VERSION 5.7 ;
  NOWIREEXTENSIONATPIN ON ;
  DIVIDERCHAR "/" ;
  BUSBITCHARS "[]" ;
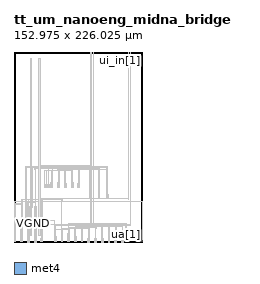
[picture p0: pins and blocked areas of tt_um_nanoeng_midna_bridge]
MACRO tt_um_nanoeng_midna_bridge
  CLASS BLOCK ;
  FOREIGN tt_um_nanoeng_midna_bridge ;
  ORIGIN 0.215 0.265 ;
  SIZE 152.975 BY 226.025 ;
  PIN ua[0]
    DIRECTION INOUT ;
    USE ANALOG ;
    PORT
      LAYER met4 ;
        RECT 151.810 0.000 152.710 1.000 ;
    END
  END ua[0]
  PIN ua[1]
    DIRECTION INOUT ;
    USE ANALOG ;
    ANTENNAGATEAREA 1.200000 ;
    PORT
      LAYER met4 ;
        RECT 132.490 0.000 133.390 1.000 ;
    END
  END ua[1]
  PIN ui_in[0]
    DIRECTION INPUT ;
    USE SIGNAL ;
    ANTENNAGATEAREA 1.800000 ;
    PORT
      LAYER met4 ;
        RECT 138.310 224.760 138.610 225.760 ;
    END
  END ui_in[0]
  PIN ui_in[1]
    DIRECTION INPUT ;
    USE SIGNAL ;
    ANTENNAGATEAREA 0.300000 ;
    PORT
      LAYER met4 ;
        RECT 135.550 224.760 135.850 225.760 ;
    END
  END ui_in[1]
  PIN uo_out[0]
    DIRECTION OUTPUT ;
    USE SIGNAL ;
    ANTENNAGATEAREA 1.200000 ;
    PORT
      LAYER met4 ;
        RECT 94.150 224.760 94.450 225.760 ;
    END
  END uo_out[0]
  PIN uo_out[1]
    DIRECTION OUTPUT ;
    USE SIGNAL ;
    ANTENNAGATEAREA 1.200000 ;
    PORT
      LAYER met4 ;
        RECT 91.390 224.760 91.690 225.760 ;
    END
  END uo_out[1]
  PIN VGND
    DIRECTION INPUT ;
    USE GROUND ;
    PORT
      LAYER met4 ;
        RECT 19.250 21.300 20.750 22.700 ;
    END
  END VGND
  PIN VPWR
    DIRECTION INPUT ;
    USE POWER ;
    PORT
      LAYER met4 ;
        RECT 29.250 21.300 30.750 22.700 ;
    END
  END VPWR
  OBS
      LAYER pwell ;
        RECT 35.785 64.785 41.645 67.785 ;
      LAYER nwell ;
        RECT 43.735 64.735 45.995 70.925 ;
        RECT 51.735 64.735 53.995 70.925 ;
      LAYER pwell ;
        RECT 59.785 64.785 61.795 68.785 ;
      LAYER nwell ;
        RECT 67.735 64.735 69.995 70.925 ;
      LAYER pwell ;
        RECT 75.785 64.785 77.795 68.785 ;
      LAYER nwell ;
        RECT 89.735 52.735 91.995 64.925 ;
        RECT 99.735 52.735 101.845 64.925 ;
      LAYER pwell ;
        RECT 109.785 52.785 111.795 56.785 ;
        RECT -0.215 -0.215 1.795 21.785 ;
        RECT 7.785 -0.215 9.795 21.785 ;
      LAYER nwell ;
        RECT 15.735 -0.265 17.845 41.925 ;
        RECT 23.735 -0.265 25.995 41.925 ;
      LAYER pwell ;
        RECT 31.785 -0.215 33.795 3.785 ;
        RECT 47.785 -0.215 49.795 5.785 ;
        RECT 55.785 -0.215 57.795 9.785 ;
        RECT 63.785 -0.215 65.795 9.785 ;
        RECT 71.785 -0.215 73.795 5.785 ;
        RECT 79.785 -0.215 81.795 5.785 ;
      LAYER nwell ;
        RECT 87.735 -0.265 89.845 3.925 ;
        RECT 95.735 -0.265 97.845 3.925 ;
        RECT 103.735 -0.265 105.845 3.925 ;
        RECT 111.735 -0.265 113.845 3.925 ;
        RECT 119.735 -0.265 121.845 5.925 ;
        RECT 127.735 -0.265 129.845 5.925 ;
      LAYER li1 ;
        RECT 43.915 70.575 45.815 70.745 ;
        RECT 35.915 67.485 41.515 67.655 ;
        RECT 35.915 65.085 36.085 67.485 ;
        RECT 36.715 66.975 40.715 67.145 ;
        RECT 36.485 65.765 36.655 66.805 ;
        RECT 40.775 65.765 40.945 66.805 ;
        RECT 36.715 65.425 40.715 65.595 ;
        RECT 41.345 65.085 41.515 67.485 ;
        RECT 35.915 64.915 41.515 65.085 ;
        RECT 43.915 65.085 44.085 70.575 ;
        RECT 44.700 70.065 45.030 70.235 ;
        RECT 44.485 65.810 44.655 69.850 ;
        RECT 45.075 65.810 45.245 69.850 ;
        RECT 44.700 65.425 45.030 65.595 ;
        RECT 45.645 65.085 45.815 70.575 ;
        RECT 43.915 64.915 45.815 65.085 ;
        RECT 51.915 70.575 53.815 70.745 ;
        RECT 51.915 65.085 52.085 70.575 ;
        RECT 52.700 70.065 53.030 70.235 ;
        RECT 52.485 65.810 52.655 69.850 ;
        RECT 53.075 65.810 53.245 69.850 ;
        RECT 52.700 65.425 53.030 65.595 ;
        RECT 53.645 65.085 53.815 70.575 ;
        RECT 67.915 70.575 69.815 70.745 ;
        RECT 51.915 64.915 53.815 65.085 ;
        RECT 59.915 68.485 61.665 68.655 ;
        RECT 59.915 65.085 60.085 68.485 ;
        RECT 60.625 67.975 60.955 68.145 ;
        RECT 60.485 65.765 60.655 67.805 ;
        RECT 60.925 65.765 61.095 67.805 ;
        RECT 60.625 65.425 60.955 65.595 ;
        RECT 61.495 65.085 61.665 68.485 ;
        RECT 59.915 64.915 61.665 65.085 ;
        RECT 67.915 65.085 68.085 70.575 ;
        RECT 68.700 70.065 69.030 70.235 ;
        RECT 68.485 65.810 68.655 69.850 ;
        RECT 69.075 65.810 69.245 69.850 ;
        RECT 68.700 65.425 69.030 65.595 ;
        RECT 69.645 65.085 69.815 70.575 ;
        RECT 67.915 64.915 69.815 65.085 ;
        RECT 75.915 68.485 77.665 68.655 ;
        RECT 75.915 65.085 76.085 68.485 ;
        RECT 76.625 67.975 76.955 68.145 ;
        RECT 76.485 65.765 76.655 67.805 ;
        RECT 76.925 65.765 77.095 67.805 ;
        RECT 76.625 65.425 76.955 65.595 ;
        RECT 77.495 65.085 77.665 68.485 ;
        RECT 75.915 64.915 77.665 65.085 ;
        RECT 89.915 64.575 91.815 64.745 ;
        RECT 89.915 53.085 90.085 64.575 ;
        RECT 90.700 64.065 91.030 64.235 ;
        RECT 90.485 53.810 90.655 63.850 ;
        RECT 91.075 53.810 91.245 63.850 ;
        RECT 90.700 53.425 91.030 53.595 ;
        RECT 91.645 53.085 91.815 64.575 ;
        RECT 89.915 52.915 91.815 53.085 ;
        RECT 99.915 64.575 101.665 64.745 ;
        RECT 99.915 53.085 100.085 64.575 ;
        RECT 100.625 64.065 100.955 64.235 ;
        RECT 100.485 53.810 100.655 63.850 ;
        RECT 100.925 53.810 101.095 63.850 ;
        RECT 100.625 53.425 100.955 53.595 ;
        RECT 101.495 53.085 101.665 64.575 ;
        RECT 99.915 52.915 101.665 53.085 ;
        RECT 109.915 56.485 111.665 56.655 ;
        RECT 109.915 53.085 110.085 56.485 ;
        RECT 110.625 55.975 110.955 56.145 ;
        RECT 110.485 53.765 110.655 55.805 ;
        RECT 110.925 53.765 111.095 55.805 ;
        RECT 110.625 53.425 110.955 53.595 ;
        RECT 111.495 53.085 111.665 56.485 ;
        RECT 109.915 52.915 111.665 53.085 ;
        RECT 15.915 41.575 17.665 41.745 ;
        RECT -0.085 21.485 1.665 21.655 ;
        RECT -0.085 0.085 0.085 21.485 ;
        RECT 0.625 20.975 0.955 21.145 ;
        RECT 0.485 0.765 0.655 20.805 ;
        RECT 0.925 0.765 1.095 20.805 ;
        RECT 0.625 0.425 0.955 0.595 ;
        RECT 1.495 0.085 1.665 21.485 ;
        RECT -0.085 -0.085 1.665 0.085 ;
        RECT 7.915 21.485 9.665 21.655 ;
        RECT 7.915 0.085 8.085 21.485 ;
        RECT 8.625 20.975 8.955 21.145 ;
        RECT 8.485 0.765 8.655 20.805 ;
        RECT 8.925 0.765 9.095 20.805 ;
        RECT 8.625 0.425 8.955 0.595 ;
        RECT 9.495 0.085 9.665 21.485 ;
        RECT 7.915 -0.085 9.665 0.085 ;
        RECT 15.915 0.085 16.085 41.575 ;
        RECT 16.625 41.065 16.955 41.235 ;
        RECT 16.485 0.810 16.655 40.850 ;
        RECT 16.925 0.810 17.095 40.850 ;
        RECT 16.625 0.425 16.955 0.595 ;
        RECT 17.495 0.085 17.665 41.575 ;
        RECT 15.915 -0.085 17.665 0.085 ;
        RECT 23.915 41.575 25.815 41.745 ;
        RECT 23.915 0.085 24.085 41.575 ;
        RECT 24.700 41.065 25.030 41.235 ;
        RECT 24.485 0.810 24.655 40.850 ;
        RECT 25.075 0.810 25.245 40.850 ;
        RECT 24.700 0.425 25.030 0.595 ;
        RECT 25.645 0.085 25.815 41.575 ;
        RECT 55.915 9.485 57.665 9.655 ;
        RECT 47.915 5.485 49.665 5.655 ;
        RECT 23.915 -0.085 25.815 0.085 ;
        RECT 31.915 3.485 33.665 3.655 ;
        RECT 31.915 0.085 32.085 3.485 ;
        RECT 32.625 2.975 32.955 3.145 ;
        RECT 32.485 0.765 32.655 2.805 ;
        RECT 32.925 0.765 33.095 2.805 ;
        RECT 32.625 0.425 32.955 0.595 ;
        RECT 33.495 0.085 33.665 3.485 ;
        RECT 31.915 -0.085 33.665 0.085 ;
        RECT 47.915 0.085 48.085 5.485 ;
        RECT 48.625 4.975 48.955 5.145 ;
        RECT 48.485 0.765 48.655 4.805 ;
        RECT 48.925 0.765 49.095 4.805 ;
        RECT 48.625 0.425 48.955 0.595 ;
        RECT 49.495 0.085 49.665 5.485 ;
        RECT 47.915 -0.085 49.665 0.085 ;
        RECT 55.915 0.085 56.085 9.485 ;
        RECT 56.625 8.975 56.955 9.145 ;
        RECT 56.485 0.765 56.655 8.805 ;
        RECT 56.925 0.765 57.095 8.805 ;
        RECT 56.625 0.425 56.955 0.595 ;
        RECT 57.495 0.085 57.665 9.485 ;
        RECT 55.915 -0.085 57.665 0.085 ;
        RECT 63.915 9.485 65.665 9.655 ;
        RECT 63.915 0.085 64.085 9.485 ;
        RECT 64.625 8.975 64.955 9.145 ;
        RECT 64.485 0.765 64.655 8.805 ;
        RECT 64.925 0.765 65.095 8.805 ;
        RECT 64.625 0.425 64.955 0.595 ;
        RECT 65.495 0.085 65.665 9.485 ;
        RECT 63.915 -0.085 65.665 0.085 ;
        RECT 71.915 5.485 73.665 5.655 ;
        RECT 71.915 0.085 72.085 5.485 ;
        RECT 72.625 4.975 72.955 5.145 ;
        RECT 72.485 0.765 72.655 4.805 ;
        RECT 72.925 0.765 73.095 4.805 ;
        RECT 72.625 0.425 72.955 0.595 ;
        RECT 73.495 0.085 73.665 5.485 ;
        RECT 71.915 -0.085 73.665 0.085 ;
        RECT 79.915 5.485 81.665 5.655 ;
        RECT 79.915 0.085 80.085 5.485 ;
        RECT 80.625 4.975 80.955 5.145 ;
        RECT 80.485 0.765 80.655 4.805 ;
        RECT 80.925 0.765 81.095 4.805 ;
        RECT 80.625 0.425 80.955 0.595 ;
        RECT 81.495 0.085 81.665 5.485 ;
        RECT 119.915 5.575 121.665 5.745 ;
        RECT 79.915 -0.085 81.665 0.085 ;
        RECT 87.915 3.575 89.665 3.745 ;
        RECT 87.915 0.085 88.085 3.575 ;
        RECT 88.625 3.065 88.955 3.235 ;
        RECT 88.485 0.810 88.655 2.850 ;
        RECT 88.925 0.810 89.095 2.850 ;
        RECT 88.625 0.425 88.955 0.595 ;
        RECT 89.495 0.085 89.665 3.575 ;
        RECT 87.915 -0.085 89.665 0.085 ;
        RECT 95.915 3.575 97.665 3.745 ;
        RECT 95.915 0.085 96.085 3.575 ;
        RECT 96.625 3.065 96.955 3.235 ;
        RECT 96.485 0.810 96.655 2.850 ;
        RECT 96.925 0.810 97.095 2.850 ;
        RECT 96.625 0.425 96.955 0.595 ;
        RECT 97.495 0.085 97.665 3.575 ;
        RECT 95.915 -0.085 97.665 0.085 ;
        RECT 103.915 3.575 105.665 3.745 ;
        RECT 103.915 0.085 104.085 3.575 ;
        RECT 104.625 3.065 104.955 3.235 ;
        RECT 104.485 0.810 104.655 2.850 ;
        RECT 104.925 0.810 105.095 2.850 ;
        RECT 104.625 0.425 104.955 0.595 ;
        RECT 105.495 0.085 105.665 3.575 ;
        RECT 103.915 -0.085 105.665 0.085 ;
        RECT 111.915 3.575 113.665 3.745 ;
        RECT 111.915 0.085 112.085 3.575 ;
        RECT 112.625 3.065 112.955 3.235 ;
        RECT 112.485 0.810 112.655 2.850 ;
        RECT 112.925 0.810 113.095 2.850 ;
        RECT 112.625 0.425 112.955 0.595 ;
        RECT 113.495 0.085 113.665 3.575 ;
        RECT 111.915 -0.085 113.665 0.085 ;
        RECT 119.915 0.085 120.085 5.575 ;
        RECT 120.625 5.065 120.955 5.235 ;
        RECT 120.485 0.810 120.655 4.850 ;
        RECT 120.925 0.810 121.095 4.850 ;
        RECT 120.625 0.425 120.955 0.595 ;
        RECT 121.495 0.085 121.665 5.575 ;
        RECT 119.915 -0.085 121.665 0.085 ;
        RECT 127.915 5.575 129.665 5.745 ;
        RECT 127.915 0.085 128.085 5.575 ;
        RECT 128.625 5.065 128.955 5.235 ;
        RECT 128.485 0.810 128.655 4.850 ;
        RECT 128.925 0.810 129.095 4.850 ;
        RECT 128.625 0.425 128.955 0.595 ;
        RECT 129.495 0.085 129.665 5.575 ;
        RECT 127.915 -0.085 129.665 0.085 ;
      LAYER met1 ;
        RECT 45.280 90.300 45.680 90.700 ;
        RECT 53.280 90.300 53.680 90.700 ;
        RECT 69.280 90.300 69.680 90.700 ;
        RECT 91.280 90.300 91.680 90.700 ;
        RECT 40.980 89.300 41.380 89.700 ;
        RECT 13.800 88.300 14.200 88.700 ;
        RECT 21.800 87.300 22.200 87.700 ;
        RECT 24.665 86.300 25.065 86.700 ;
        RECT 9.030 49.300 9.430 49.700 ;
        RECT 17.030 49.300 17.430 49.700 ;
        RECT 0.370 47.300 0.770 47.700 ;
        RECT 0.495 24.700 0.645 47.300 ;
        RECT 1.030 44.300 1.430 44.700 ;
        RECT 8.150 44.300 8.550 44.700 ;
        RECT 0.130 24.300 0.645 24.700 ;
        RECT 0.255 20.785 0.405 24.300 ;
        RECT 0.495 21.175 0.645 24.300 ;
        RECT 0.645 20.945 0.935 21.175 ;
        RECT 1.155 20.785 1.305 44.300 ;
        RECT 8.275 20.785 8.425 44.300 ;
        RECT 8.590 20.860 8.990 21.260 ;
        RECT 9.155 20.785 9.305 49.300 ;
        RECT 16.150 46.300 16.550 46.700 ;
        RECT 16.275 40.830 16.425 46.300 ;
        RECT 16.590 40.950 16.990 41.350 ;
        RECT 17.155 40.830 17.305 49.300 ;
        RECT 24.790 41.265 24.940 86.300 ;
        RECT 36.050 84.300 36.450 84.700 ;
        RECT 38.515 84.300 38.915 84.700 ;
        RECT 36.175 66.785 36.325 84.300 ;
        RECT 38.640 67.175 38.790 84.300 ;
        RECT 36.735 66.945 40.695 67.175 ;
        RECT 41.105 66.785 41.255 89.300 ;
        RECT 44.050 84.300 44.450 84.700 ;
        RECT 44.665 84.300 45.065 84.700 ;
        RECT 44.175 69.830 44.325 84.300 ;
        RECT 44.790 70.265 44.940 84.300 ;
        RECT 44.720 70.035 45.010 70.265 ;
        RECT 45.405 69.830 45.555 90.300 ;
        RECT 52.050 85.300 52.450 85.700 ;
        RECT 52.175 69.830 52.325 85.300 ;
        RECT 52.665 84.300 53.065 84.700 ;
        RECT 52.790 70.265 52.940 84.300 ;
        RECT 52.720 70.035 53.010 70.265 ;
        RECT 53.405 69.830 53.555 90.300 ;
        RECT 61.130 89.300 61.530 89.700 ;
        RECT 60.050 85.300 60.450 85.700 ;
        RECT 60.590 85.300 60.990 85.700 ;
        RECT 36.455 65.785 36.685 66.785 ;
        RECT 40.745 65.785 40.975 66.785 ;
        RECT 44.455 65.830 44.685 69.830 ;
        RECT 45.045 65.830 45.275 69.830 ;
        RECT 52.455 65.830 52.685 69.830 ;
        RECT 53.045 65.830 53.275 69.830 ;
        RECT 60.175 67.785 60.325 85.300 ;
        RECT 60.715 68.175 60.865 85.300 ;
        RECT 60.645 67.945 60.935 68.175 ;
        RECT 61.255 67.785 61.405 89.300 ;
        RECT 68.050 88.300 68.450 88.700 ;
        RECT 68.175 69.830 68.325 88.300 ;
        RECT 68.665 84.300 69.065 84.700 ;
        RECT 68.790 70.265 68.940 84.300 ;
        RECT 68.720 70.035 69.010 70.265 ;
        RECT 69.405 69.830 69.555 90.300 ;
        RECT 77.130 89.300 77.530 89.700 ;
        RECT 76.050 88.300 76.450 88.700 ;
        RECT 76.590 88.300 76.990 88.700 ;
        RECT 60.455 65.785 60.685 67.785 ;
        RECT 60.895 65.785 61.125 67.785 ;
        RECT 68.455 65.830 68.685 69.830 ;
        RECT 69.045 65.830 69.275 69.830 ;
        RECT 76.175 67.785 76.325 88.300 ;
        RECT 76.715 68.175 76.865 88.300 ;
        RECT 76.645 67.945 76.935 68.175 ;
        RECT 77.255 67.785 77.405 89.300 ;
        RECT 90.050 86.300 90.450 86.700 ;
        RECT 90.665 86.300 91.065 86.700 ;
        RECT 76.455 65.785 76.685 67.785 ;
        RECT 76.895 65.785 77.125 67.785 ;
        RECT 36.735 65.395 40.695 65.625 ;
        RECT 44.720 65.395 45.010 65.625 ;
        RECT 52.720 65.395 53.010 65.625 ;
        RECT 60.645 65.395 60.935 65.625 ;
        RECT 68.720 65.395 69.010 65.625 ;
        RECT 76.645 65.395 76.935 65.625 ;
        RECT 90.175 63.830 90.325 86.300 ;
        RECT 90.790 64.265 90.940 86.300 ;
        RECT 90.720 64.035 91.010 64.265 ;
        RECT 91.405 63.830 91.555 90.300 ;
        RECT 111.130 89.300 111.530 89.700 ;
        RECT 100.050 87.300 100.450 87.700 ;
        RECT 100.590 87.300 100.990 87.700 ;
        RECT 110.050 87.300 110.450 87.700 ;
        RECT 100.175 63.830 100.325 87.300 ;
        RECT 100.715 64.265 100.865 87.300 ;
        RECT 101.130 86.300 101.530 86.700 ;
        RECT 100.645 64.035 100.935 64.265 ;
        RECT 101.255 63.830 101.405 86.300 ;
        RECT 90.455 53.830 90.685 63.830 ;
        RECT 91.045 53.830 91.275 63.830 ;
        RECT 100.455 53.830 100.685 63.830 ;
        RECT 100.895 53.830 101.125 63.830 ;
        RECT 110.175 55.785 110.325 87.300 ;
        RECT 110.590 85.300 110.990 85.700 ;
        RECT 110.715 56.175 110.865 85.300 ;
        RECT 110.645 55.945 110.935 56.175 ;
        RECT 111.255 55.785 111.405 89.300 ;
        RECT 110.455 53.785 110.685 55.785 ;
        RECT 110.895 53.785 111.125 55.785 ;
        RECT 90.720 53.395 91.010 53.625 ;
        RECT 100.645 53.395 100.935 53.625 ;
        RECT 110.645 53.395 110.935 53.625 ;
        RECT 32.590 50.300 32.990 50.700 ;
        RECT 32.150 47.300 32.550 47.700 ;
        RECT 25.180 46.300 25.580 46.700 ;
        RECT 24.720 41.035 25.010 41.265 ;
        RECT 25.305 40.830 25.455 46.300 ;
        RECT 0.455 0.785 0.685 20.785 ;
        RECT 0.895 0.785 1.125 20.785 ;
        RECT 8.455 0.785 8.685 20.785 ;
        RECT 8.895 0.785 9.125 20.785 ;
        RECT 16.455 0.830 16.685 40.830 ;
        RECT 16.895 0.830 17.125 40.830 ;
        RECT 24.455 20.700 24.685 40.830 ;
        RECT 24.370 20.300 24.770 20.700 ;
        RECT 24.455 0.830 24.685 20.300 ;
        RECT 25.045 0.830 25.275 40.830 ;
        RECT 32.275 2.785 32.425 47.300 ;
        RECT 32.715 3.175 32.865 50.300 ;
        RECT 33.030 49.300 33.430 49.700 ;
        RECT 56.590 49.300 56.990 49.700 ;
        RECT 32.645 2.945 32.935 3.175 ;
        RECT 33.155 2.785 33.305 49.300 ;
        RECT 48.130 24.300 48.530 24.700 ;
        RECT 48.255 4.785 48.405 24.300 ;
        RECT 48.590 19.300 48.990 19.700 ;
        RECT 48.715 5.175 48.865 19.300 ;
        RECT 49.030 14.300 49.430 14.700 ;
        RECT 56.150 14.300 56.550 14.700 ;
        RECT 48.645 4.945 48.935 5.175 ;
        RECT 49.155 4.785 49.305 14.300 ;
        RECT 56.275 8.785 56.425 14.300 ;
        RECT 56.715 9.175 56.865 49.300 ;
        RECT 64.590 21.300 64.990 21.700 ;
        RECT 57.030 15.300 57.430 15.700 ;
        RECT 56.645 8.945 56.935 9.175 ;
        RECT 57.155 8.785 57.305 15.300 ;
        RECT 64.150 14.300 64.550 14.700 ;
        RECT 64.275 8.785 64.425 14.300 ;
        RECT 64.715 9.175 64.865 21.300 ;
        RECT 88.150 20.300 88.550 20.700 ;
        RECT 96.150 20.300 96.550 20.700 ;
        RECT 104.150 20.300 104.550 20.700 ;
        RECT 112.150 20.300 112.550 20.700 ;
        RECT 120.150 20.300 120.550 20.700 ;
        RECT 128.150 20.300 128.550 20.700 ;
        RECT 72.590 18.300 72.990 18.700 ;
        RECT 81.030 18.300 81.430 18.700 ;
        RECT 65.030 16.300 65.430 16.700 ;
        RECT 64.645 8.945 64.935 9.175 ;
        RECT 65.155 8.785 65.305 16.300 ;
        RECT 72.150 15.300 72.550 15.700 ;
        RECT 32.455 0.785 32.685 2.785 ;
        RECT 32.895 0.785 33.125 2.785 ;
        RECT 48.455 0.785 48.685 4.785 ;
        RECT 48.895 0.785 49.125 4.785 ;
        RECT 56.455 0.785 56.685 8.785 ;
        RECT 56.895 0.785 57.125 8.785 ;
        RECT 64.455 0.785 64.685 8.785 ;
        RECT 64.895 0.785 65.125 8.785 ;
        RECT 72.275 4.785 72.425 15.300 ;
        RECT 72.715 5.175 72.865 18.300 ;
        RECT 73.030 17.300 73.430 17.700 ;
        RECT 80.590 17.300 80.990 17.700 ;
        RECT 72.645 4.945 72.935 5.175 ;
        RECT 73.155 4.785 73.305 17.300 ;
        RECT 80.150 16.300 80.550 16.700 ;
        RECT 80.275 4.785 80.425 16.300 ;
        RECT 80.715 5.175 80.865 17.300 ;
        RECT 80.645 4.945 80.935 5.175 ;
        RECT 81.155 4.785 81.305 18.300 ;
        RECT 72.455 0.785 72.685 4.785 ;
        RECT 72.895 0.785 73.125 4.785 ;
        RECT 80.455 0.785 80.685 4.785 ;
        RECT 80.895 0.785 81.125 4.785 ;
        RECT 88.275 2.830 88.425 20.300 ;
        RECT 88.590 19.300 88.990 19.700 ;
        RECT 88.715 3.265 88.865 19.300 ;
        RECT 89.030 15.300 89.430 15.700 ;
        RECT 88.645 3.035 88.935 3.265 ;
        RECT 89.155 2.830 89.305 15.300 ;
        RECT 96.275 2.830 96.425 20.300 ;
        RECT 96.590 19.300 96.990 19.700 ;
        RECT 96.715 3.265 96.865 19.300 ;
        RECT 97.030 16.300 97.430 16.700 ;
        RECT 96.645 3.035 96.935 3.265 ;
        RECT 97.155 2.830 97.305 16.300 ;
        RECT 104.275 2.830 104.425 20.300 ;
        RECT 104.590 19.300 104.990 19.700 ;
        RECT 104.715 3.265 104.865 19.300 ;
        RECT 105.030 17.300 105.430 17.700 ;
        RECT 104.645 3.035 104.935 3.265 ;
        RECT 105.155 2.830 105.305 17.300 ;
        RECT 112.275 2.830 112.425 20.300 ;
        RECT 112.590 19.300 112.990 19.700 ;
        RECT 112.715 3.265 112.865 19.300 ;
        RECT 113.030 18.300 113.430 18.700 ;
        RECT 112.645 3.035 112.935 3.265 ;
        RECT 113.155 2.830 113.305 18.300 ;
        RECT 120.275 4.830 120.425 20.300 ;
        RECT 120.590 18.300 120.990 18.700 ;
        RECT 120.715 5.265 120.865 18.300 ;
        RECT 121.030 17.300 121.430 17.700 ;
        RECT 120.645 5.035 120.935 5.265 ;
        RECT 121.155 4.830 121.305 17.300 ;
        RECT 128.275 4.830 128.425 20.300 ;
        RECT 129.030 18.300 129.430 18.700 ;
        RECT 128.590 17.300 128.990 17.700 ;
        RECT 128.715 5.265 128.865 17.300 ;
        RECT 128.645 5.035 128.935 5.265 ;
        RECT 129.155 4.830 129.305 18.300 ;
        RECT 88.455 0.830 88.685 2.830 ;
        RECT 88.895 0.830 89.125 2.830 ;
        RECT 96.455 0.830 96.685 2.830 ;
        RECT 96.895 0.830 97.125 2.830 ;
        RECT 104.455 0.830 104.685 2.830 ;
        RECT 104.895 0.830 105.125 2.830 ;
        RECT 112.455 0.830 112.685 2.830 ;
        RECT 112.895 0.830 113.125 2.830 ;
        RECT 120.455 0.830 120.685 4.830 ;
        RECT 120.895 0.830 121.125 4.830 ;
        RECT 128.455 0.830 128.685 4.830 ;
        RECT 128.895 0.830 129.125 4.830 ;
        RECT 0.580 0.395 1.000 0.625 ;
        RECT 8.645 0.395 8.935 0.625 ;
        RECT 16.645 0.395 16.935 0.625 ;
        RECT 24.720 0.395 25.010 0.625 ;
        RECT 32.580 0.395 33.000 0.625 ;
        RECT 48.580 0.395 49.000 0.625 ;
        RECT 56.580 0.395 57.000 0.625 ;
        RECT 64.580 0.395 65.000 0.625 ;
        RECT 72.580 0.395 73.000 0.625 ;
        RECT 80.580 0.395 81.000 0.625 ;
        RECT 88.580 0.395 89.000 0.625 ;
        RECT 96.580 0.395 97.000 0.625 ;
        RECT 104.580 0.395 105.000 0.625 ;
        RECT 112.580 0.395 113.000 0.625 ;
        RECT 120.580 0.395 121.000 0.625 ;
        RECT 128.580 0.395 129.000 0.625 ;
      LAYER met2 ;
        RECT 29.725 91.075 30.275 91.275 ;
        RECT 29.725 90.925 44.000 91.075 ;
        RECT 45.280 90.925 91.680 91.075 ;
        RECT 29.725 90.725 30.275 90.925 ;
        RECT 45.280 90.300 45.680 90.925 ;
        RECT 53.280 90.300 53.680 90.925 ;
        RECT 69.280 90.300 69.680 90.925 ;
        RECT 91.280 90.300 91.680 90.925 ;
        RECT 19.725 90.075 20.275 90.275 ;
        RECT 19.725 89.925 111.530 90.075 ;
        RECT 19.725 89.725 20.275 89.925 ;
        RECT 40.980 89.300 41.380 89.925 ;
        RECT 61.130 89.300 61.530 89.925 ;
        RECT 77.130 89.300 77.530 89.925 ;
        RECT 111.130 89.300 111.530 89.925 ;
        RECT 14.000 88.925 76.990 89.075 ;
        RECT 13.800 88.300 14.200 88.700 ;
        RECT 68.050 88.300 68.450 88.925 ;
        RECT 76.050 88.300 76.450 88.925 ;
        RECT 76.590 88.300 76.990 88.925 ;
        RECT 22.000 87.925 110.450 88.075 ;
        RECT 21.800 87.300 22.200 87.700 ;
        RECT 100.050 87.300 100.450 87.925 ;
        RECT 100.590 87.300 100.990 87.925 ;
        RECT 110.050 87.300 110.450 87.925 ;
        RECT 24.665 86.925 101.530 87.075 ;
        RECT 24.665 86.300 25.065 86.925 ;
        RECT 90.050 86.300 90.450 86.925 ;
        RECT 90.665 86.300 91.065 86.925 ;
        RECT 101.130 86.300 101.530 86.925 ;
        RECT 52.050 85.925 110.990 86.075 ;
        RECT 52.050 85.300 52.450 85.925 ;
        RECT 60.050 85.300 60.450 85.925 ;
        RECT 60.590 85.300 60.990 85.925 ;
        RECT 110.590 85.300 110.990 85.925 ;
        RECT 36.050 84.925 69.065 85.075 ;
        RECT 36.050 84.300 36.450 84.925 ;
        RECT 38.515 84.300 38.915 84.925 ;
        RECT 44.050 84.300 44.450 84.925 ;
        RECT 44.665 84.300 45.065 84.925 ;
        RECT 52.665 84.300 53.065 84.925 ;
        RECT 68.665 84.300 69.065 84.925 ;
        RECT 135.425 51.075 135.975 51.275 ;
        RECT 32.290 50.925 136.200 51.075 ;
        RECT 32.590 50.300 32.990 50.925 ;
        RECT 135.425 50.725 135.975 50.925 ;
        RECT 9.030 49.925 56.990 50.075 ;
        RECT 9.030 49.300 9.430 49.925 ;
        RECT 17.030 49.300 17.430 49.925 ;
        RECT 33.030 49.300 33.430 49.925 ;
        RECT 56.590 49.300 56.990 49.925 ;
        RECT 151.985 48.075 152.535 48.275 ;
        RECT 0.370 47.925 32.550 48.075 ;
        RECT 32.770 47.925 152.760 48.075 ;
        RECT 0.370 47.300 0.770 47.925 ;
        RECT 32.150 47.300 32.550 47.925 ;
        RECT 151.985 47.725 152.535 47.925 ;
        RECT 16.150 46.925 25.580 47.075 ;
        RECT 16.150 46.300 16.550 46.925 ;
        RECT 25.180 46.300 25.580 46.925 ;
        RECT 1.030 44.925 8.550 45.075 ;
        RECT 1.030 44.300 1.430 44.925 ;
        RECT 8.150 44.300 8.550 44.925 ;
        RECT 16.590 41.225 16.990 41.350 ;
        RECT 21.800 41.225 22.200 41.350 ;
        RECT 16.590 41.075 22.200 41.225 ;
        RECT 16.590 40.950 16.990 41.075 ;
        RECT 21.800 40.950 22.200 41.075 ;
        RECT 19.725 25.075 20.275 25.275 ;
        RECT 0.130 24.925 48.530 25.075 ;
        RECT 0.130 24.300 0.530 24.925 ;
        RECT 19.725 24.725 20.275 24.925 ;
        RECT 48.130 24.300 48.530 24.925 ;
        RECT 132.665 22.075 133.215 22.275 ;
        RECT 64.290 21.925 133.440 22.075 ;
        RECT 64.590 21.300 64.990 21.925 ;
        RECT 132.665 21.725 133.215 21.925 ;
        RECT 8.590 21.135 8.990 21.260 ;
        RECT 13.800 21.135 14.200 21.260 ;
        RECT 8.590 20.985 14.200 21.135 ;
        RECT 29.725 21.075 30.275 21.275 ;
        RECT 8.590 20.860 8.990 20.985 ;
        RECT 13.800 20.860 14.200 20.985 ;
        RECT 24.370 20.300 24.770 21.075 ;
        RECT 29.725 20.925 128.550 21.075 ;
        RECT 29.725 20.725 30.275 20.925 ;
        RECT 88.150 20.300 88.550 20.925 ;
        RECT 96.150 20.300 96.550 20.925 ;
        RECT 104.150 20.300 104.550 20.925 ;
        RECT 112.150 20.300 112.550 20.925 ;
        RECT 120.150 20.300 120.550 20.925 ;
        RECT 128.150 20.300 128.550 20.925 ;
        RECT 138.185 20.075 138.735 20.275 ;
        RECT 48.590 19.925 138.960 20.075 ;
        RECT 48.590 19.300 48.990 19.925 ;
        RECT 88.590 19.300 88.990 19.925 ;
        RECT 96.590 19.300 96.990 19.925 ;
        RECT 104.590 19.300 104.990 19.925 ;
        RECT 112.590 19.300 112.990 19.925 ;
        RECT 138.185 19.725 138.735 19.925 ;
        RECT 91.265 19.075 91.815 19.275 ;
        RECT 72.590 18.925 129.430 19.075 ;
        RECT 72.590 18.300 72.990 18.925 ;
        RECT 81.030 18.300 81.430 18.925 ;
        RECT 91.265 18.725 91.815 18.925 ;
        RECT 113.030 18.300 113.430 18.925 ;
        RECT 120.590 18.300 120.990 18.925 ;
        RECT 129.030 18.300 129.430 18.925 ;
        RECT 94.025 18.075 94.575 18.275 ;
        RECT 73.030 17.925 128.990 18.075 ;
        RECT 73.030 17.300 73.430 17.925 ;
        RECT 80.590 17.300 80.990 17.925 ;
        RECT 94.025 17.725 94.575 17.925 ;
        RECT 105.030 17.300 105.430 17.925 ;
        RECT 121.030 17.300 121.430 17.925 ;
        RECT 128.590 17.300 128.990 17.925 ;
        RECT 65.030 16.925 97.430 17.075 ;
        RECT 65.030 16.300 65.430 16.925 ;
        RECT 80.150 16.300 80.550 16.925 ;
        RECT 97.030 16.300 97.430 16.925 ;
        RECT 57.030 15.925 89.430 16.075 ;
        RECT 57.030 15.300 57.430 15.925 ;
        RECT 72.150 15.300 72.550 15.925 ;
        RECT 89.030 15.300 89.430 15.925 ;
        RECT 49.030 14.925 64.550 15.075 ;
        RECT 49.030 14.300 49.430 14.925 ;
        RECT 56.150 14.300 56.550 14.925 ;
        RECT 64.150 14.300 64.550 14.925 ;
      LAYER met3 ;
        RECT 29.725 90.725 30.275 91.275 ;
        RECT 19.725 89.725 20.275 90.275 ;
        RECT 13.725 20.785 14.275 88.775 ;
        RECT 21.725 40.875 22.275 87.775 ;
        RECT 135.425 50.725 135.975 51.275 ;
        RECT 151.985 47.725 152.535 48.275 ;
        RECT 19.725 24.725 20.275 25.275 ;
        RECT 132.665 21.725 133.215 22.275 ;
        RECT 29.725 20.725 30.275 21.275 ;
        RECT 138.185 19.725 138.735 20.275 ;
        RECT 91.265 18.725 91.815 19.275 ;
        RECT 94.025 17.725 94.575 18.275 ;
      LAYER met4 ;
        RECT 91.340 224.760 91.390 225.260 ;
        RECT 91.690 224.760 91.740 225.260 ;
        RECT 19.250 22.700 20.750 217.760 ;
        RECT 29.250 22.700 30.750 217.760 ;
        RECT 19.250 8.000 20.750 21.300 ;
        RECT 29.250 8.000 30.750 21.300 ;
        RECT 91.340 19.275 91.740 224.760 ;
        RECT 94.100 224.760 94.150 225.260 ;
        RECT 94.450 224.760 94.500 225.260 ;
        RECT 91.265 18.725 91.815 19.275 ;
        RECT 94.100 18.275 94.500 224.760 ;
        RECT 135.500 224.760 135.550 225.260 ;
        RECT 135.850 224.760 135.900 225.260 ;
        RECT 135.500 51.275 135.900 224.760 ;
        RECT 138.260 224.760 138.310 225.260 ;
        RECT 138.610 224.760 138.660 225.260 ;
        RECT 135.425 50.725 135.975 51.275 ;
        RECT 132.665 21.725 133.215 22.275 ;
        RECT 94.025 17.725 94.575 18.275 ;
        RECT 132.740 1.000 133.140 21.725 ;
        RECT 138.260 20.275 138.660 224.760 ;
        RECT 151.985 47.725 152.535 48.275 ;
        RECT 138.185 19.725 138.735 20.275 ;
        RECT 152.060 1.000 152.460 47.725 ;
  END
END tt_um_nanoeng_midna_bridge
END LIBRARY

